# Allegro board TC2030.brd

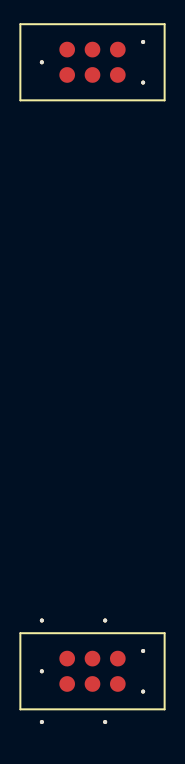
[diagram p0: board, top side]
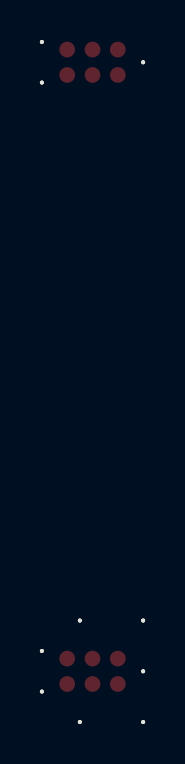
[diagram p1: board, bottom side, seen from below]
No outline. copper layers: TOP, BOTTOM. Coordinates in mm from the lowest, leftmost part position.

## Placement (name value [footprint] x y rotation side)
NOREF  -  [unnamed]  0 0 0 top
NOREF#2  -  [unnamed#2]  0 30.48 0 top

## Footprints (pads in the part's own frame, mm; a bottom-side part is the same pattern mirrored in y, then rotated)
unnamed
  round 0.201 hole 2.375 unplated: (-2.54,2.54) (-2.54,-2.54) (0.635,2.54) (0.635,-2.54)
  round 0.201 hole 0.991 unplated: (-2.54,0) (2.54,1.016) (2.54,-1.016)
  round 0.787 smd: 1(-1.27,-0.635) 2(-1.27,0.635) 3(0,-0.635) 4(0,0.635) 5(1.27,-0.635) 6(1.27,0.635)
unnamed#2
  round 0.201 hole 0.991 unplated: (-2.54,0) (2.54,1.016) (2.54,-1.016)
  round 0.787 smd: 1(-1.27,-0.635) 2(-1.27,0.635) 3(0,-0.635) 4(0,0.635) 5(1.27,-0.635) 6(1.27,0.635)

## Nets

Pads without a net: NOREF 1 2 3 4 5 6; NOREF#2 1 2 3 4 5 6

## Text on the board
NCLEGEND-1-2: FIGURE | SIZE | 0.991 | 2.375 | DRILL CHART: TOP to BOTTOM | ALL UNITS ARE IN MILLIMETERS | TOLERANCE | +0.076/-0.076 | PLATED | NON-PLATED | QTY | 6 | 4
